VERSION 5.8 ;
BUSBITCHARS "[]" ;
DIVIDERCHAR "/" ;
UNITS
    DATABASE MICRONS 1000 ;
END UNITS

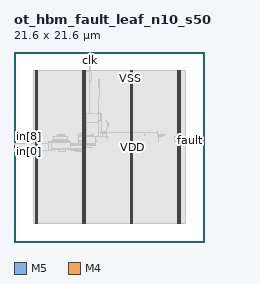
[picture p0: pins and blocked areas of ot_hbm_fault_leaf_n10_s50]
MACRO ot_hbm_fault_leaf_n10_s50
  FOREIGN ot_hbm_fault_leaf_n10_s50 0 0 ;
  CLASS BLOCK ;
  SIZE 21.6 BY 21.6 ;
  PIN clk
    DIRECTION INPUT ;
    USE SIGNAL ;
    PORT
      LAYER M5 ;
        RECT  8.592 21.516 8.616 21.6 ;
    END
  END clk
  PIN fault
    DIRECTION OUTPUT ;
    USE SIGNAL ;
    PORT
      LAYER M4 ;
        RECT  21.516 11.568 21.6 11.592 ;
    END
  END fault
  PIN in[0]
    DIRECTION INPUT ;
    USE SIGNAL ;
    PORT
      LAYER M4 ;
        RECT  0 10.32 0.084 10.344 ;
    END
  END in[0]
  PIN in[1]
    DIRECTION INPUT ;
    USE SIGNAL ;
    PORT
      LAYER M4 ;
        RECT  0 10.416 0.084 10.44 ;
    END
  END in[1]
  PIN in[2]
    DIRECTION INPUT ;
    USE SIGNAL ;
    PORT
      LAYER M4 ;
        RECT  0 10.512 0.084 10.536 ;
    END
  END in[2]
  PIN in[3]
    DIRECTION INPUT ;
    USE SIGNAL ;
    PORT
      LAYER M4 ;
        RECT  0 10.608 0.084 10.632 ;
    END
  END in[3]
  PIN in[4]
    DIRECTION INPUT ;
    USE SIGNAL ;
    PORT
      LAYER M4 ;
        RECT  0 10.704 0.084 10.728 ;
    END
  END in[4]
  PIN in[5]
    DIRECTION INPUT ;
    USE SIGNAL ;
    PORT
      LAYER M4 ;
        RECT  0 10.8 0.084 10.824 ;
    END
  END in[5]
  PIN in[6]
    DIRECTION INPUT ;
    USE SIGNAL ;
    PORT
      LAYER M4 ;
        RECT  0 10.896 0.084 10.92 ;
    END
  END in[6]
  PIN in[7]
    DIRECTION INPUT ;
    USE SIGNAL ;
    PORT
      LAYER M4 ;
        RECT  0 10.992 0.084 11.016 ;
    END
  END in[7]
  PIN in[8]
    DIRECTION INPUT ;
    USE SIGNAL ;
    PORT
      LAYER M4 ;
        RECT  0 11.088 0.084 11.112 ;
    END
  END in[8]
  PIN in[9]
    DIRECTION INPUT ;
    USE SIGNAL ;
    PORT
      LAYER M4 ;
        RECT  0 11.184 0.084 11.208 ;
    END
  END in[9]
  PIN rst_n
    DIRECTION INPUT ;
    USE SIGNAL ;
    PORT
      LAYER M5 ;
        RECT  8.688 21.516 8.712 21.6 ;
    END
  END rst_n
  PIN VDD
    DIRECTION INOUT ;
    USE POWER ;
    PORT
      LAYER M5 ;
        RECT  18.792 2.151 18.912 19.449 ;
        RECT  13.392 2.151 13.512 19.449 ;
        RECT  7.992 2.151 8.112 19.449 ;
        RECT  2.592 2.151 2.712 19.449 ;
    END
  END VDD
  PIN VSS
    DIRECTION INOUT ;
    USE GROUND ;
    PORT
      LAYER M5 ;
        RECT  18.6 2.137 18.72 19.463 ;
        RECT  13.2 2.137 13.32 19.463 ;
        RECT  7.8 2.137 7.92 19.463 ;
        RECT  2.4 2.137 2.52 19.463 ;
    END
  END VSS
  OBS
    LAYER RVTN ;
     RECT  2.16 2.16 19.44 2.295 ;
     RECT  2.16 2.565 19.44 2.835 ;
     RECT  2.16 3.105 19.44 3.375 ;
     RECT  2.16 3.645 19.44 3.915 ;
     RECT  2.16 4.185 19.44 4.455 ;
     RECT  2.16 4.725 19.44 4.995 ;
     RECT  2.16 5.265 19.44 5.535 ;
     RECT  2.16 5.805 19.44 6.075 ;
     RECT  2.16 6.345 19.44 6.615 ;
     RECT  2.16 6.885 19.44 7.155 ;
     RECT  2.16 7.425 19.44 7.695 ;
     RECT  2.16 7.965 19.44 8.235 ;
     RECT  2.16 8.505 19.44 8.775 ;
     RECT  2.16 9.045 19.44 9.315 ;
     RECT  2.16 9.585 19.44 9.855 ;
     RECT  2.16 10.125 19.44 10.395 ;
     RECT  2.16 10.665 19.44 10.935 ;
     RECT  2.16 11.205 19.44 11.475 ;
     RECT  2.16 11.745 19.44 12.015 ;
     RECT  2.16 12.285 19.44 12.555 ;
     RECT  2.16 12.825 19.44 13.095 ;
     RECT  2.16 13.365 19.44 13.635 ;
     RECT  2.16 13.905 19.44 14.175 ;
     RECT  2.16 14.445 19.44 14.715 ;
     RECT  2.16 14.985 19.44 15.255 ;
     RECT  2.16 15.525 19.44 15.795 ;
     RECT  2.16 16.065 19.44 16.335 ;
     RECT  2.16 16.605 19.44 16.875 ;
     RECT  2.16 17.145 19.44 17.415 ;
     RECT  2.16 17.685 19.44 17.955 ;
     RECT  2.16 18.225 19.44 18.495 ;
     RECT  2.16 18.765 19.44 19.035 ;
     RECT  2.16 19.305 19.44 19.44 ;
    LAYER RVTP ;
     RECT  2.16 2.295 19.44 2.565 ;
     RECT  2.16 2.835 19.44 3.105 ;
     RECT  2.16 3.375 19.44 3.645 ;
     RECT  2.16 3.915 19.44 4.185 ;
     RECT  2.16 4.455 19.44 4.725 ;
     RECT  2.16 4.995 19.44 5.265 ;
     RECT  2.16 5.535 19.44 5.805 ;
     RECT  2.16 6.075 19.44 6.345 ;
     RECT  2.16 6.615 19.44 6.885 ;
     RECT  2.16 7.155 19.44 7.425 ;
     RECT  2.16 7.695 19.44 7.965 ;
     RECT  2.16 8.235 19.44 8.505 ;
     RECT  2.16 8.775 19.44 9.045 ;
     RECT  2.16 9.315 19.44 9.585 ;
     RECT  2.16 9.855 19.44 10.125 ;
     RECT  2.16 10.395 19.44 10.665 ;
     RECT  2.16 10.935 19.44 11.205 ;
     RECT  2.16 11.475 19.44 11.745 ;
     RECT  2.16 12.015 19.44 12.285 ;
     RECT  2.16 12.555 19.44 12.825 ;
     RECT  2.16 13.095 19.44 13.365 ;
     RECT  2.16 13.635 19.44 13.905 ;
     RECT  2.16 14.175 19.44 14.445 ;
     RECT  2.16 14.715 19.44 14.985 ;
     RECT  2.16 15.255 19.44 15.525 ;
     RECT  2.16 15.795 19.44 16.065 ;
     RECT  2.16 16.335 19.44 16.605 ;
     RECT  2.16 16.875 19.44 17.145 ;
     RECT  2.16 17.415 19.44 17.685 ;
     RECT  2.16 17.955 19.44 18.225 ;
     RECT  2.16 18.495 19.44 18.765 ;
     RECT  2.16 19.035 19.44 19.305 ;
    LAYER M1 ;
     RECT  2.16 2.151 19.44 19.449 ;
    LAYER M2 ;
     RECT  2.16 2.151 19.44 19.449 ;
     RECT  19.44 11.376 21.515 11.394 ;
    LAYER M3 ;
     RECT  2.415 2.143 2.505 2.413 ;
     RECT  7.815 2.143 7.905 2.413 ;
     RECT  13.215 2.143 13.305 2.413 ;
     RECT  18.615 2.143 18.705 2.413 ;
     RECT  2.415 2.413 2.697 10.315 ;
     RECT  5.004 10.291 5.022 10.327 ;
     RECT  7.815 2.413 8.097 10.327 ;
     RECT  2.304 10.315 2.697 10.399 ;
     RECT  6.948 10.327 8.097 10.399 ;
     RECT  4.248 10.411 4.266 10.471 ;
     RECT  5.004 10.327 5.814 10.471 ;
     RECT  6.552 10.399 8.097 10.471 ;
     RECT  2.304 10.399 2.862 10.597 ;
     RECT  3.96 10.471 8.097 10.597 ;
     RECT  2.304 10.597 8.097 10.705 ;
     RECT  0.144 10.651 0.162 10.829 ;
     RECT  2.304 10.705 8.802 10.939 ;
     RECT  2.304 10.939 8.91 11.011 ;
     RECT  2.304 11.011 9.234 11.129 ;
     RECT  2.304 11.129 2.697 11.165 ;
     RECT  3.78 11.129 9.234 11.201 ;
     RECT  3.888 11.201 6.426 11.357 ;
     RECT  18.615 2.413 18.897 11.371 ;
     RECT  3.888 11.357 6.282 11.399 ;
     RECT  3.96 11.399 6.282 11.435 ;
     RECT  7.344 11.201 9.234 11.443 ;
     RECT  4.392 11.435 6.282 11.507 ;
     RECT  7.344 11.443 9.342 11.543 ;
     RECT  21.492 11.371 21.51 11.597 ;
     RECT  4.392 11.507 6.138 11.705 ;
     RECT  10.584 11.821 10.602 11.911 ;
     RECT  4.5 11.705 6.138 11.939 ;
     RECT  7.344 11.543 9.234 11.939 ;
     RECT  10.512 11.911 10.602 11.939 ;
     RECT  18.216 11.371 18.897 11.939 ;
     RECT  4.5 11.939 5.742 11.975 ;
     RECT  10.512 11.939 10.53 11.995 ;
     RECT  16.452 11.443 16.47 12.019 ;
     RECT  7.344 11.939 9.054 12.047 ;
     RECT  16.452 12.019 16.866 12.055 ;
     RECT  4.86 11.975 5.742 12.083 ;
     RECT  7.38 12.047 9.054 12.083 ;
     RECT  4.896 12.083 5.742 12.209 ;
     RECT  8.82 12.083 9.054 12.209 ;
     RECT  14.832 12.091 14.85 12.209 ;
     RECT  16.272 12.055 17.082 12.209 ;
     RECT  4.896 12.209 4.914 12.245 ;
     RECT  8.82 12.209 8.91 12.245 ;
     RECT  7.38 12.083 8.097 12.317 ;
     RECT  8.82 12.245 8.838 12.317 ;
     RECT  10.044 11.995 10.53 12.325 ;
     RECT  9.9 12.325 10.53 12.365 ;
     RECT  10.044 12.365 10.53 12.509 ;
     RECT  16.272 12.209 16.29 12.509 ;
     RECT  10.512 12.509 10.53 12.749 ;
     RECT  10.62 12.865 10.638 13.135 ;
     RECT  7.815 12.317 8.097 13.483 ;
     RECT  7.815 13.483 8.226 13.559 ;
     RECT  10.62 13.135 10.71 13.559 ;
     RECT  10.548 13.675 10.566 13.829 ;
     RECT  9.612 13.771 9.63 13.981 ;
     RECT  9.612 13.981 9.918 14.215 ;
     RECT  9.576 14.215 9.918 14.639 ;
     RECT  9.576 14.639 9.774 14.675 ;
     RECT  9.576 14.675 9.594 16.411 ;
     RECT  9.576 16.411 9.774 16.439 ;
     RECT  9.756 16.439 9.774 17.609 ;
     RECT  7.815 13.559 8.097 18.235 ;
     RECT  9.648 17.617 9.666 18.419 ;
     RECT  7.815 18.235 8.694 18.455 ;
     RECT  2.415 11.165 2.697 19.187 ;
     RECT  7.815 18.455 8.097 19.187 ;
     RECT  13.215 2.413 13.497 19.187 ;
     RECT  18.615 11.939 18.897 19.187 ;
     RECT  8.82 18.571 8.838 19.229 ;
     RECT  8.676 19.336 8.694 19.373 ;
     RECT  2.415 19.187 2.505 19.457 ;
     RECT  7.815 19.187 7.905 19.457 ;
     RECT  13.215 19.187 13.305 19.457 ;
     RECT  18.615 19.187 18.705 19.457 ;
    LAYER M4 ;
     RECT  0.06 10.32 2.408 11.208 ;
     RECT  2.408 2.148 2.512 19.452 ;
     RECT  2.512 2.418 2.704 19.182 ;
     RECT  2.704 10.416 3.877 11.208 ;
     RECT  3.877 10.416 4.277 11.352 ;
     RECT  4.277 10.608 6.437 11.352 ;
     RECT  6.437 10.608 7.808 11.016 ;
     RECT  7.621 12 7.808 12.024 ;
     RECT  7.808 2.148 7.912 19.452 ;
     RECT  7.912 2.418 8.104 19.368 ;
     RECT  8.104 10.992 8.243 12.024 ;
     RECT  8.104 13.488 8.243 13.608 ;
     RECT  8.104 18.24 8.705 18.264 ;
     RECT  8.104 19.344 8.749 19.368 ;
     RECT  8.243 11.232 9.209 12.024 ;
     RECT  8.243 13.584 9.596 13.608 ;
     RECT  8.104 14.64 9.596 14.664 ;
     RECT  9.209 12 9.637 12.024 ;
     RECT  9.596 13.584 9.785 14.664 ;
     RECT  9.785 13.584 9.923 14.28 ;
     RECT  9.923 14.256 9.929 14.28 ;
     RECT  9.637 12 10.073 12.504 ;
     RECT  10.073 12.48 13.208 12.504 ;
     RECT  13.208 2.148 13.312 19.452 ;
     RECT  13.312 2.418 13.504 19.182 ;
     RECT  13.504 12.48 16.301 12.504 ;
     RECT  18.608 2.148 18.712 19.452 ;
     RECT  18.712 2.418 18.904 19.182 ;
     RECT  21.481 11.568 21.564 11.592 ;
    LAYER M5 ;
     RECT  2.4 2.137 2.52 2.151 ;
     RECT  7.8 2.137 7.92 2.151 ;
     RECT  13.2 2.137 13.32 2.151 ;
     RECT  18.6 2.137 18.72 2.151 ;
     RECT  7.8 2.151 8.112 10.981 ;
     RECT  7.8 10.981 8.232 11.365 ;
     RECT  7.8 11.365 8.28 12.035 ;
     RECT  9.888 12.325 9.912 12.469 ;
     RECT  9.648 12.469 9.912 13.811 ;
     RECT  9.888 13.811 9.912 14.291 ;
     RECT  7.8 12.035 8.232 14.629 ;
     RECT  7.8 14.629 8.616 19.333 ;
     RECT  2.4 2.151 2.712 19.449 ;
     RECT  13.2 2.151 13.512 19.449 ;
     RECT  18.6 2.151 18.912 19.449 ;
     RECT  2.4 19.449 2.52 19.463 ;
     RECT  7.8 19.333 8.712 19.463 ;
     RECT  13.2 19.449 13.32 19.463 ;
     RECT  18.6 19.449 18.72 19.463 ;
     RECT  8.592 19.463 8.712 21.584 ;
  END
END ot_hbm_fault_leaf_n10_s50
END LIBRARY
